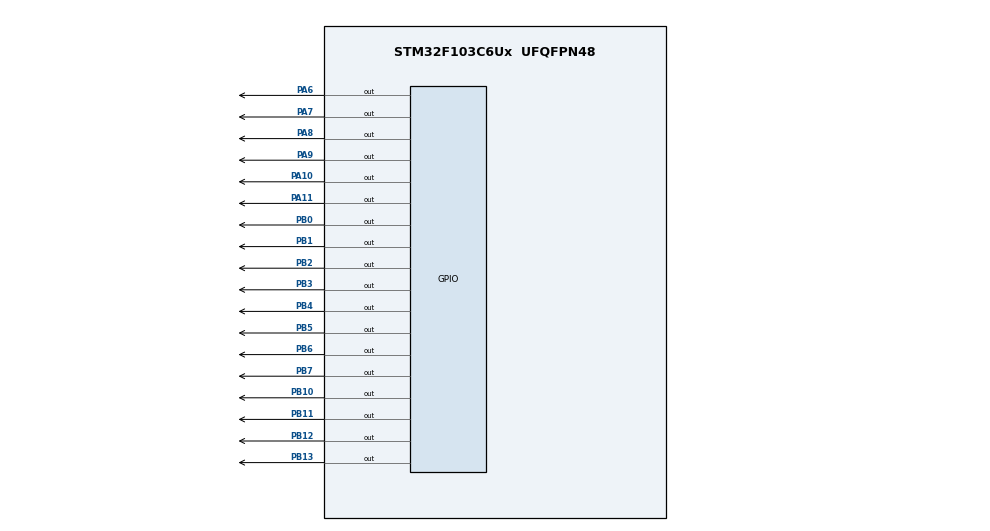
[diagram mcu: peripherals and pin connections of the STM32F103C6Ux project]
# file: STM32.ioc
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Mcu.Family=STM32F1
Mcu.Name=STM32F103C6Ux
Mcu.Package=UFQFPN48
NVIC.PriorityGroup=NVIC_PRIORITYGROUP_4
PA10.Signal=GPIO_Output
PA11.Signal=GPIO_Output
PA6.Signal=GPIO_Output
PA7.Signal=GPIO_Output
PA8.Signal=GPIO_Output
PA9.Signal=GPIO_Output
PB0.Signal=GPIO_Output
PB1.Signal=GPIO_Output
PB10.Signal=GPIO_Output
PB11.Signal=GPIO_Output
PB12.Signal=GPIO_Output
PB13.Signal=GPIO_Output
PB2.Signal=GPIO_Output
PB3.Signal=GPIO_Output
PB4.Signal=GPIO_Output
PB5.Signal=GPIO_Output
PB6.Signal=GPIO_Output
PB7.Signal=GPIO_Output
ProjectManager.HeapSize=0x200
ProjectManager.StackSize=0x400
ProjectManager.TargetToolchain=STM32CubeIDE
RCC.APB1Freq_Value=8000000
RCC.APB2Freq_Value=8000000
VP_SYS_VS_ND.Mode=No_Debug
board=custom

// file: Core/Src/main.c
/* USER CODE BEGIN Header */
/**
  ******************************************************************************
  * @file           : main.c
  * @brief          : Main program body
  ******************************************************************************
  * @attention

  *
  * <h2><center>&copy; Copyright (c) 2024 STMicroelectronics.
  * All rights reserved.</center></h2>
  *
  * This software component is licensed by ST under BSD 3-Clause license,
  * the "License"; You may not use this file except in compliance with the
  * License. You may obtain a copy of the License at:
  *                        opensource.org/licenses/BSD-3-Clause
  *
  ******************************************************************************
  */
/* USER CODE END Header */
#include "main.h"

void SystemClock_Config(void);
static void MX_GPIO_Init(void);

int demRed = 5, demYellow = 2, demGreen = 3 , phuong = 1;
 void display7SEG_ngang(int num)
 {
	  if(num == 0)
	  {
		  HAL_GPIO_WritePin(GPIOB, GPIO_PIN_0, 0);
		  HAL_GPIO_WritePin(GPIOB, GPIO_PIN_1, 0);
		  HAL_GPIO_WritePin(GPIOB, GPIO_PIN_2, 0);
		  HAL_GPIO_WritePin(GPIOB, GPIO_PIN_3, 0);
		  HAL_GPIO_WritePin(GPIOB, GPIO_PIN_4, 0);
		  HAL_GPIO_WritePin(GPIOB, GPIO_PIN_5, 0);
		  HAL_GPIO_WritePin(GPIOB, GPIO_PIN_6, 1);
	  }
	  if(num == 1)
	  {
		  HAL_GPIO_WritePin(GPIOB, GPIO_PIN_0, 1);
		  HAL_GPIO_WritePin(GPIOB, GPIO_PIN_1, 0);
		  HAL_GPIO_WritePin(GPIOB, GPIO_PIN_2, 0);
		  HAL_GPIO_WritePin(GPIOB, GPIO_PIN_3, 1);
		  HAL_GPIO_WritePin(GPIOB, GPIO_PIN_4, 1);
		  HAL_GPIO_WritePin(GPIOB, GPIO_PIN_5, 1);
		  HAL_GPIO_WritePin(GPIOB, GPIO_PIN_6, 1);
	  }
	  if(num == 2)
	  	  {
	  		  HAL_GPIO_WritePin(GPIOB, GPIO_PIN_0, 0);
	  		  HAL_GPIO_WritePin(GPIOB, GPIO_PIN_1, 0);
	  		  HAL_GPIO_WritePin(GPIOB, GPIO_PIN_2, 1);
	  		  HAL_GPIO_WritePin(GPIOB, GPIO_PIN_3, 0);
	  		  HAL_GPIO_WritePin(GPIOB, GPIO_PIN_4, 0);
	  		  HAL_GPIO_WritePin(GPIOB, GPIO_PIN_5, 1);
	  		  HAL_GPIO_WritePin(GPIOB, GPIO_PIN_6, 0);
	  	  }
	  if(num == 3)
	  	  {
	  		  HAL_GPIO_WritePin(GPIOB, GPIO_PIN_0, 0);
	  		  HAL_GPIO_WritePin(GPIOB, GPIO_PIN_1, 0);
	  		  HAL_GPIO_WritePin(GPIOB, GPIO_PIN_2, 0);
	  		  HAL_GPIO_WritePin(GPIOB, GPIO_PIN_3, 0);
	  		  HAL_GPIO_WritePin(GPIOB, GPIO_PIN_4, 1);
	  		  HAL_GPIO_WritePin(GPIOB, GPIO_PIN_5, 1);
	  		  HAL_GPIO_WritePin(GPIOB, GPIO_PIN_6, 0);
	  	  }
	  if(num == 4)
	  	  {
	  		  HAL_GPIO_WritePin(GPIOB, GPIO_PIN_0, 1);
	  		  HAL_GPIO_WritePin(GPIOB, GPIO_PIN_1, 0);
	  		  HAL_GPIO_WritePin(GPIOB, GPIO_PIN_2, 0);
	  		  HAL_GPIO_WritePin(GPIOB, GPIO_PIN_3, 1);
	  		  HAL_GPIO_WritePin(GPIOB, GPIO_PIN_4, 1);
	  		  HAL_GPIO_WritePin(GPIOB, GPIO_PIN_5, 0);
	  		  HAL_GPIO_WritePin(GPIOB, GPIO_PIN_6, 0);
	  	  }
	  if(num == 5)
	  	  {
	  		  HAL_GPIO_WritePin(GPIOB, GPIO_PIN_0, 0);
	  		  HAL_GPIO_WritePin(GPIOB, GPIO_PIN_1, 1);
	  		  HAL_GPIO_WritePin(GPIOB, GPIO_PIN_2, 0);
	  		  HAL_GPIO_WritePin(GPIOB, GPIO_PIN_3, 0);
	  		  HAL_GPIO_WritePin(GPIOB, GPIO_PIN_4, 1);
	  		  HAL_GPIO_WritePin(GPIOB, GPIO_PIN_5, 0);
	  		  HAL_GPIO_WritePin(GPIOB, GPIO_PIN_6, 0);
	  	  }
	  if(num == 6)
	  	  {
	  		  HAL_GPIO_WritePin(GPIOB, GPIO_PIN_0, 0);
	  		  HAL_GPIO_WritePin(GPIOB, GPIO_PIN_1, 1);
	  		  HAL_GPIO_WritePin(GPIOB, GPIO_PIN_2, 0);
	  		  HAL_GPIO_WritePin(GPIOB, GPIO_PIN_3, 0);
	  		  HAL_GPIO_WritePin(GPIOB, GPIO_PIN_4, 0);
	  		  HAL_GPIO_WritePin(GPIOB, GPIO_PIN_5, 0);
	  		  HAL_GPIO_WritePin(GPIOB, GPIO_PIN_6, 0);
	  	  }
	  if(num == 7)
	  	  {
	  		  HAL_GPIO_WritePin(GPIOB, GPIO_PIN_0, 0);
	  		  HAL_GPIO_WritePin(GPIOB, GPIO_PIN_1, 0);
	  		  HAL_GPIO_WritePin(GPIOB, GPIO_PIN_2, 0);
	  		  HAL_GPIO_WritePin(GPIOB, GPIO_PIN_3, 1);
	  		  HAL_GPIO_WritePin(GPIOB, GPIO_PIN_4, 1);
	  		  HAL_GPIO_WritePin(GPIOB, GPIO_PIN_5, 1);
	  		  HAL_GPIO_WritePin(GPIOB, GPIO_PIN_6, 1);
	  	  }
	  if(num == 8)
	  	  {
	  		  HAL_GPIO_WritePin(GPIOB, GPIO_PIN_0, 0);
	  		  HAL_GPIO_WritePin(GPIOB, GPIO_PIN_1, 0);
	  		  HAL_GPIO_WritePin(GPIOB, GPIO_PIN_2, 0);
	  		  HAL_GPIO_WritePin(GPIOB, GPIO_PIN_3, 0);
	  		  HAL_GPIO_WritePin(GPIOB, GPIO_PIN_4, 0);
	  		  HAL_GPIO_WritePin(GPIOB, GPIO_PIN_5, 0);
	  		  HAL_GPIO_WritePin(GPIOB, GPIO_PIN_6, 0);
	  	  }
	  if(num == 9)
	  	  {
	  		  HAL_GPIO_WritePin(GPIOB, GPIO_PIN_0, 0);
	  		  HAL_GPIO_WritePin(GPIOB, GPIO_PIN_1, 0);
	  		  HAL_GPIO_WritePin(GPIOB, GPIO_PIN_2, 0);
	  		  HAL_GPIO_WritePin(GPIOB, GPIO_PIN_3, 0);
	  		  HAL_GPIO_WritePin(GPIOB, GPIO_PIN_4, 1);
	  		  HAL_GPIO_WritePin(GPIOB, GPIO_PIN_5, 0);
	  		  HAL_GPIO_WritePin(GPIOB, GPIO_PIN_6, 0);
	  	  }
 }

  	void display7SEG_doc(int num)
  	  {
  		  if(num == 0)
  		  {
  			  HAL_GPIO_WritePin(GPIOB, GPIO_PIN_7, 0);
  			  HAL_GPIO_WritePin(GPIOB, GPIO_PIN_8, 0);
  			  HAL_GPIO_WritePin(GPIOB, GPIO_PIN_9, 0);
  			  HAL_GPIO_WritePin(GPIOB, GPIO_PIN_10, 0);
  			  HAL_GPIO_WritePin(GPIOB, GPIO_PIN_11, 0);
  			  HAL_GPIO_WritePin(GPIOB, GPIO_PIN_12, 0);
  			  HAL_GPIO_WritePin(GPIOB, GPIO_PIN_13, 1);
  		  }
  		  if(num == 1)
  		  {
  			  HAL_GPIO_WritePin(GPIOB, GPIO_PIN_7, 1);
  			  HAL_GPIO_WritePin(GPIOB, GPIO_PIN_8, 0);
  			  HAL_GPIO_WritePin(GPIOB, GPIO_PIN_9, 0);
  			  HAL_GPIO_WritePin(GPIOB, GPIO_PIN_10, 1);
  			  HAL_GPIO_WritePin(GPIOB, GPIO_PIN_11, 1);
  			  HAL_GPIO_WritePin(GPIOB, GPIO_PIN_12, 1);
  			  HAL_GPIO_WritePin(GPIOB, GPIO_PIN_13, 1);
  		  }
  		  if(num == 2)
  		  	  {
  		  		  HAL_GPIO_WritePin(GPIOB, GPIO_PIN_7, 0);
  		  		  HAL_GPIO_WritePin(GPIOB, GPIO_PIN_8, 0);
  		  		  HAL_GPIO_WritePin(GPIOB, GPIO_PIN_9, 1);
  		  		  HAL_GPIO_WritePin(GPIOB, GPIO_PIN_10, 0);
  		  		  HAL_GPIO_WritePin(GPIOB, GPIO_PIN_11, 0);
  		  		  HAL_GPIO_WritePin(GPIOB, GPIO_PIN_12, 1);
  		  		  HAL_GPIO_WritePin(GPIOB, GPIO_PIN_13, 0);
  		  	  }
  		  if(num == 3)
  		  	  {
  		  		  HAL_GPIO_WritePin(GPIOB, GPIO_PIN_7, 0);
  		  		  HAL_GPIO_WritePin(GPIOB, GPIO_PIN_8, 0);
  		  		  HAL_GPIO_WritePin(GPIOB, GPIO_PIN_9, 0);
  		  		  HAL_GPIO_WritePin(GPIOB, GPIO_PIN_10, 0);
  		  		  HAL_GPIO_WritePin(GPIOB, GPIO_PIN_11, 1);
  		  		  HAL_GPIO_WritePin(GPIOB, GPIO_PIN_12, 1);
  		  		  HAL_GPIO_WritePin(GPIOB, GPIO_PIN_13, 0);
  		  	  }
  		  if(num == 4)
  		  	  {
  		  		  HAL_GPIO_WritePin(GPIOB, GPIO_PIN_7, 1);
  		  		  HAL_GPIO_WritePin(GPIOB, GPIO_PIN_8, 0);
  		  		  HAL_GPIO_WritePin(GPIOB, GPIO_PIN_9, 0);
  		  		  HAL_GPIO_WritePin(GPIOB, GPIO_PIN_10, 1);
  		  		  HAL_GPIO_WritePin(GPIOB, GPIO_PIN_11, 1);
  		  		  HAL_GPIO_WritePin(GPIOB, GPIO_PIN_12, 0);
  		  		  HAL_GPIO_WritePin(GPIOB, GPIO_PIN_13, 0);
  		  	  }
  		  if(num == 5)
  		  	  {
  		  		  HAL_GPIO_WritePin(GPIOB, GPIO_PIN_7, 0);
  		  		  HAL_GPIO_WritePin(GPIOB, GPIO_PIN_8, 1);
  		  		  HAL_GPIO_WritePin(GPIOB, GPIO_PIN_9, 0);
  		  		  HAL_GPIO_WritePin(GPIOB, GPIO_PIN_10, 0);
  		  		  HAL_GPIO_WritePin(GPIOB, GPIO_PIN_11, 1);
  		  		  HAL_GPIO_WritePin(GPIOB, GPIO_PIN_12, 0);
  		  		  HAL_GPIO_WritePin(GPIOB, GPIO_PIN_13, 0);
  		  	  }
  		  if(num == 6)
  		  	  {
  		  		  HAL_GPIO_WritePin(GPIOB, GPIO_PIN_7, 0);
  		  		  HAL_GPIO_WritePin(GPIOB, GPIO_PIN_8, 1);
  		  		  HAL_GPIO_WritePin(GPIOB, GPIO_PIN_9, 0);
  		  		  HAL_GPIO_WritePin(GPIOB, GPIO_PIN_10, 0);
  		  		  HAL_GPIO_WritePin(GPIOB, GPIO_PIN_11, 0);
  		  		  HAL_GPIO_WritePin(GPIOB, GPIO_PIN_12, 0);
  		  		  HAL_GPIO_WritePin(GPIOB, GPIO_PIN_13, 0);
  		  	  }
  		  if(num == 7)
  		  	  {
  		  		  HAL_GPIO_WritePin(GPIOB, GPIO_PIN_7, 0);
  		  		  HAL_GPIO_WritePin(GPIOB, GPIO_PIN_8, 0);
  		  		  HAL_GPIO_WritePin(GPIOB, GPIO_PIN_9, 0);
  		  		  HAL_GPIO_WritePin(GPIOB, GPIO_PIN_10, 1);
  		  		  HAL_GPIO_WritePin(GPIOB, GPIO_PIN_11, 1);
  		  		  HAL_GPIO_WritePin(GPIOB, GPIO_PIN_12, 1);
  		  		  HAL_GPIO_WritePin(GPIOB, GPIO_PIN_13, 1);
  		  	  }
  		  if(num == 8)
  		  	  {
  		  		  HAL_GPIO_WritePin(GPIOB, GPIO_PIN_7, 0);
  		  		  HAL_GPIO_WritePin(GPIOB, GPIO_PIN_8, 0);
  		  		  HAL_GPIO_WritePin(GPIOB, GPIO_PIN_9, 0);
  		  		  HAL_GPIO_WritePin(GPIOB, GPIO_PIN_10, 0);
  		  		  HAL_GPIO_WritePin(GPIOB, GPIO_PIN_11, 0);
  		  		  HAL_GPIO_WritePin(GPIOB, GPIO_PIN_12, 0);
  		  		  HAL_GPIO_WritePin(GPIOB, GPIO_PIN_13, 0);
  		  	  }
  		  if(num == 9)
  		  	  {
  		  		  HAL_GPIO_WritePin(GPIOB, GPIO_PIN_7, 0);
  		  		  HAL_GPIO_WritePin(GPIOB, GPIO_PIN_8, 0);
  		  		  HAL_GPIO_WritePin(GPIOB, GPIO_PIN_9, 0);
  		  		  HAL_GPIO_WritePin(GPIOB, GPIO_PIN_10, 0);
  		  		  HAL_GPIO_WritePin(GPIOB, GPIO_PIN_11, 1);
  		  		  HAL_GPIO_WritePin(GPIOB, GPIO_PIN_12, 0);
  		  		  HAL_GPIO_WritePin(GPIOB, GPIO_PIN_13, 0);
  		  	  }
  	  }

int main(void)
{

  /* MCU Configuration--------------------------------------------------------*/

  /* Reset of all peripherals, Initializes the Flash interface and the Systick. */
  HAL_Init();

  /* Configure the system clock */
  SystemClock_Config();

  /* Initialize all configured peripherals */
  MX_GPIO_Init();

  /* Infinite loop */
  /* USER CODE BEGIN WHILE */
  while (1)
  {
	  if( phuong == 1)
	  	  {
	  		  if(demRed > 0)
	  		  {
	  			  display7SEG_ngang(demRed);
	  			  if (demRed >= 3 )
	  			  {
	  				  // Bật đèn đỏ cho đường ngang, xanh cho đường dọc
	  				  HAL_GPIO_WritePin(GPIOA, GPIO_PIN_10, GPIO_PIN_SET);
	  				  HAL_GPIO_WritePin(GPIOA, GPIO_PIN_9, GPIO_PIN_RESET);
	  				  HAL_GPIO_WritePin(GPIOA, GPIO_PIN_11, GPIO_PIN_RESET);

	  				  HAL_GPIO_WritePin(GPIOA, GPIO_PIN_8, GPIO_PIN_SET);
	  				  HAL_GPIO_WritePin(GPIOA, GPIO_PIN_7, GPIO_PIN_RESET);
	  				  HAL_GPIO_WritePin(GPIOA, GPIO_PIN_6, GPIO_PIN_RESET);
	  				  display7SEG_doc(demGreen);
	  				   demGreen--;
	  			  }
	  			  if(demRed < 3 && demRed >= 1)
	  			  {
	  				 // Bật đèn đ ? cho đư ?ng ngang, vàng cho đư ?ng d ?c
	  				  HAL_GPIO_WritePin(GPIOA, GPIO_PIN_10, GPIO_PIN_SET);
	  				  HAL_GPIO_WritePin(GPIOA, GPIO_PIN_9, GPIO_PIN_RESET);
	  				  HAL_GPIO_WritePin(GPIOA, GPIO_PIN_11, GPIO_PIN_RESET);

	  				  HAL_GPIO_WritePin(GPIOA, GPIO_PIN_6, GPIO_PIN_SET);
	  			      HAL_GPIO_WritePin(GPIOA, GPIO_PIN_7, GPIO_PIN_RESET);
	  		          HAL_GPIO_WritePin(GPIOA, GPIO_PIN_8, GPIO_PIN_RESET);
	  		          display7SEG_doc(demYellow);
	  		           demYellow--;
	  			  }
	  			  demRed--;

	  		  }
	  		  if (demYellow <= 0 )
	  		            {
	  		                demYellow = 2;
	  		            }
	  		            if (demGreen <= 0)
	  		            {
	  		                demGreen = 3;
	  		            }
	  		            if (demRed <= 0)
	  		            {
	  		                demRed = 5;
	  		                phuong = 2;
	  		            }
	  	  }
	  	  else
	  	  {
	  		  if( demRed > 0)
	  		  {
	  			  display7SEG_doc(demRed);
	  			  if (demRed >= 3 )
	  			  {
	  				  // Bật đèn đ ? cho đư ?ng d ?c, xanh cho đư ?ng ngang
	  				  HAL_GPIO_WritePin(GPIOA, GPIO_PIN_7, GPIO_PIN_SET);
	  				  HAL_GPIO_WritePin(GPIOA, GPIO_PIN_6, GPIO_PIN_RESET);
	  				  HAL_GPIO_WritePin(GPIOA, GPIO_PIN_8, GPIO_PIN_RESET);

	  				  HAL_GPIO_WritePin(GPIOA, GPIO_PIN_11, GPIO_PIN_SET);
	  				  HAL_GPIO_WritePin(GPIOA, GPIO_PIN_9, GPIO_PIN_RESET);
	  				  HAL_GPIO_WritePin(GPIOA, GPIO_PIN_10, GPIO_PIN_RESET);
	  				  display7SEG_ngang(demGreen);
	  				   demGreen--;

	  			  }
	  			  if(demRed < 3 && demRed >= 1)
	  			  {
	  				  // Bật đèn đ ? cho đư ?ng d ?c, vàng cho đư ?ng ngang
	  				  HAL_GPIO_WritePin(GPIOA, GPIO_PIN_7, GPIO_PIN_SET);
	  				  HAL_GPIO_WritePin(GPIOA, GPIO_PIN_6, GPIO_PIN_RESET);
	  				  HAL_GPIO_WritePin(GPIOA, GPIO_PIN_8, GPIO_PIN_RESET);

	  				  HAL_GPIO_WritePin(GPIOA, GPIO_PIN_9, GPIO_PIN_SET);
	  				  HAL_GPIO_WritePin(GPIOA, GPIO_PIN_10, GPIO_PIN_RESET);
	  				  HAL_GPIO_WritePin(GPIOA, GPIO_PIN_11, GPIO_PIN_RESET);
	  				   display7SEG_ngang(demYellow);
	  				    demYellow--;
	  			  }
	  			  demRed--;

	  	      }
	  		  if (demYellow <= 0)
	  				            {
	  				                demYellow = 2;
	  				            }
	  				            if (demGreen <= 0)
	  				            {
	  				                demGreen = 3;
	  				            }
	  				            if (demRed <= 0)
	  				            {
	  				                demRed = 5;
	  				                phuong = 1;
	  				            }

	       }

	  	  HAL_Delay(1000);

    /* USER CODE END WHILE */

  }
}

void SystemClock_Config(void)
{
  RCC_OscInitTypeDef RCC_OscInitStruct = {0};
  RCC_ClkInitTypeDef RCC_ClkInitStruct = {0};

  /** Initializes the RCC Oscillators according to the specified parameters
  * in the RCC_OscInitTypeDef structure.
  */
  RCC_OscInitStruct.OscillatorType = RCC_OSCILLATORTYPE_HSI;
  RCC_OscInitStruct.HSIState = RCC_HSI_ON;
  RCC_OscInitStruct.HSICalibrationValue = RCC_HSICALIBRATION_DEFAULT;
  RCC_OscInitStruct.PLL.PLLState = RCC_PLL_NONE;
  if (HAL_RCC_OscConfig(&RCC_OscInitStruct) != HAL_OK)
  {
    Error_Handler();
  }
  /** Initializes the CPU, AHB and APB buses clocks
  */
  RCC_ClkInitStruct.ClockType = RCC_CLOCKTYPE_HCLK|RCC_CLOCKTYPE_SYSCLK
                              |RCC_CLOCKTYPE_PCLK1|RCC_CLOCKTYPE_PCLK2;
  RCC_ClkInitStruct.SYSCLKSource = RCC_SYSCLKSOURCE_HSI;
  RCC_ClkInitStruct.AHBCLKDivider = RCC_SYSCLK_DIV1;
  RCC_ClkInitStruct.APB1CLKDivider = RCC_HCLK_DIV1;
  RCC_ClkInitStruct.APB2CLKDivider = RCC_HCLK_DIV1;

  if (HAL_RCC_ClockConfig(&RCC_ClkInitStruct, FLASH_LATENCY_0) != HAL_OK)
  {
    Error_Handler();
  }
}

static void MX_GPIO_Init(void)
{
  GPIO_InitTypeDef GPIO_InitStruct = {0};

  /* GPIO Ports Clock Enable */
  __HAL_RCC_GPIOA_CLK_ENABLE();
  __HAL_RCC_GPIOB_CLK_ENABLE();

  /*Configure GPIO pin Output Level */
  HAL_GPIO_WritePin(GPIOA, GPIO_PIN_6|GPIO_PIN_7|GPIO_PIN_8|GPIO_PIN_9
                          |GPIO_PIN_10|GPIO_PIN_11, GPIO_PIN_RESET);

  /*Configure GPIO pin Output Level */
  HAL_GPIO_WritePin(GPIOB, GPIO_PIN_0|GPIO_PIN_1|GPIO_PIN_2|GPIO_PIN_10
                          |GPIO_PIN_11|GPIO_PIN_12|GPIO_PIN_13|GPIO_PIN_3
                          |GPIO_PIN_4|GPIO_PIN_5|GPIO_PIN_6|GPIO_PIN_7
                          |GPIO_PIN_8|GPIO_PIN_9, GPIO_PIN_RESET);

  /*Configure GPIO pins : PA6 PA7 PA8 PA9
                           PA10 PA11 */
  GPIO_InitStruct.Pin = GPIO_PIN_6|GPIO_PIN_7|GPIO_PIN_8|GPIO_PIN_9
                          |GPIO_PIN_10|GPIO_PIN_11;
  GPIO_InitStruct.Mode = GPIO_MODE_OUTPUT_PP;
  GPIO_InitStruct.Pull = GPIO_NOPULL;
  GPIO_InitStruct.Speed = GPIO_SPEED_FREQ_LOW;
  HAL_GPIO_Init(GPIOA, &GPIO_InitStruct);

  /*Configure GPIO pins : PB0 PB1 PB2 PB10
                           PB11 PB12 PB13 PB3
                           PB4 PB5 PB6 PB7
                           PB8 PB9 */
  GPIO_InitStruct.Pin = GPIO_PIN_0|GPIO_PIN_1|GPIO_PIN_2|GPIO_PIN_10
                          |GPIO_PIN_11|GPIO_PIN_12|GPIO_PIN_13|GPIO_PIN_3
                          |GPIO_PIN_4|GPIO_PIN_5|GPIO_PIN_6|GPIO_PIN_7
                          |GPIO_PIN_8|GPIO_PIN_9;
  GPIO_InitStruct.Mode = GPIO_MODE_OUTPUT_PP;
  GPIO_InitStruct.Pull = GPIO_NOPULL;
  GPIO_InitStruct.Speed = GPIO_SPEED_FREQ_LOW;
  HAL_GPIO_Init(GPIOB, &GPIO_InitStruct);

}

void Error_Handler(void)
{
  __disable_irq();
  while (1)
  {
  }
}

/************************ (C) COPYRIGHT STMicroelectronics *****END OF FILE****/
